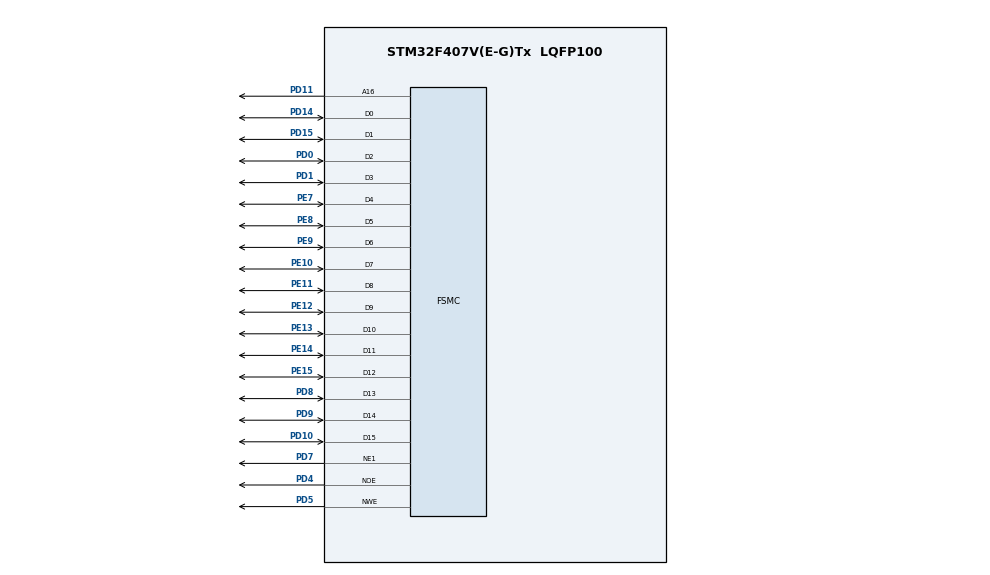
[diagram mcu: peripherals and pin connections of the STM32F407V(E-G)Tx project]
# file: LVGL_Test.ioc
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FSMC.ExtendedMode1=FSMC_EXTENDED_MODE_ENABLE
Mcu.Family=STM32F4
Mcu.Name=STM32F407V(E-G)Tx
Mcu.Package=LQFP100
NVIC.PriorityGroup=NVIC_PRIORITYGROUP_4
NVIC.TIM6_DAC_IRQn=true\:0\:0\:false\:false\:true\:true\:true
PA13.Mode=Serial_Wire
PA13.Signal=SYS_JTMS-SWDIO
PA14.Mode=Serial_Wire
PA14.Signal=SYS_JTCK-SWCLK
PD0.Mode=16b-d1
PD0.Signal=FSMC_D2
PD1.Mode=16b-d1
PD1.Signal=FSMC_D3
PD10.Mode=16b-d1
PD10.Signal=FSMC_D15
PD11.Mode=A16_1
PD11.Signal=FSMC_A16
PD14.Mode=16b-d1
PD14.Signal=FSMC_D0
PD15.Mode=16b-d1
PD15.Signal=FSMC_D1
PD4.Mode=Lcd1
PD4.Signal=FSMC_NOE
PD5.Mode=Lcd1
PD5.Signal=FSMC_NWE
PD7.Mode=NorPsramChipSelect1_1
PD7.Signal=FSMC_NE1
PD8.Mode=16b-d1
PD8.Signal=FSMC_D13
PD9.Mode=16b-d1
PD9.Signal=FSMC_D14
PE10.Mode=16b-d1
PE10.Signal=FSMC_D7
PE11.Mode=16b-d1
PE11.Signal=FSMC_D8
PE12.Mode=16b-d1
PE12.Signal=FSMC_D9
PE13.Mode=16b-d1
PE13.Signal=FSMC_D10
PE14.Mode=16b-d1
PE14.Signal=FSMC_D11
PE15.Mode=16b-d1
PE15.Signal=FSMC_D12
PE7.Mode=16b-d1
PE7.Signal=FSMC_D4
PE8.Mode=16b-d1
PE8.Signal=FSMC_D5
PE9.Mode=16b-d1
PE9.Signal=FSMC_D6
PH0-OSC_IN.Mode=HSE-External-Oscillator
PH0-OSC_IN.Signal=RCC_OSC_IN
PH1-OSC_OUT.Mode=HSE-External-Oscillator
PH1-OSC_OUT.Signal=RCC_OSC_OUT
ProjectManager.HeapSize=0x200
ProjectManager.StackSize=0x1000
ProjectManager.TargetToolchain=MDK-ARM V5
RCC.48MHZClocksFreq_Value=84000000
RCC.AHBFreq_Value=168000000
RCC.APB1CLKDivider=RCC_HCLK_DIV4
RCC.APB1Freq_Value=42000000
RCC.APB1TimFreq_Value=84000000
RCC.APB2CLKDivider=RCC_HCLK_DIV2
RCC.APB2Freq_Value=84000000
RCC.APB2TimFreq_Value=168000000
RCC.CortexFreq_Value=168000000
RCC.HCLKFreq_Value=168000000
RCC.HSE_VALUE=25000000
RCC.HSI_VALUE=16000000
RCC.LSE_VALUE=32768
RCC.PLLM=8
RCC.PLLN=168
RCC.SYSCLKFreq_VALUE=168000000
RCC.SYSCLKSource=RCC_SYSCLKSOURCE_PLLCLK
RCC.VCOOutputFreq_Value=336000000
TIM6.AutoReloadPreload=TIM_AUTORELOAD_PRELOAD_ENABLE
TIM6.Period=1000-1
TIM6.Prescaler=72-1
VP_TIM6_VS_ClockSourceINT.Mode=Enable_Timer
board=custom

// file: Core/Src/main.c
/* USER CODE BEGIN Header */
/**
  ******************************************************************************
  * @file           : main.c
  * @brief          : Main program body
  ******************************************************************************
  * @attention
  *
  * Copyright (c) 2025 STMicroelectronics.
  * All rights reserved.
  *
  * This software is licensed under terms that can be found in the LICENSE file
  * in the root directory of this software component.
  * If no LICENSE file comes with this software, it is provided AS-IS.
  *
  ******************************************************************************
  */
/* USER CODE END Header */
#include "main.h"
#include "tim.h"
#include "gpio.h"
#include "fsmc.h"
#include "lcd.h"

void SystemClock_Config(void);

int main(void)
{
  /* USER CODE BEGIN 1 */
  uint8_t x=0;
  uint8_t lcd_id[12];				//存放LCD ID字符串
  /* USER CODE END 1 */

  /* MCU Configuration--------------------------------------------------------*/

  /* Reset of all peripherals, Initializes the Flash interface and the Systick. */
  HAL_Init();

  /* USER CODE BEGIN Init */
  LCD_Init();           //初始化LCD FSMC接口
  POINT_COLOR=RED;      //画笔颜色：红色
  /* USER CODE END Init */

  /* Configure the system clock */
  SystemClock_Config();

  /* Initialize all configured peripherals */
  MX_GPIO_Init();
  MX_TIM6_Init();
  // MX_FSMC_Init();

  /* Infinite loop */
  while (1)
  {

    /* USER CODE BEGIN 3 */
	    switch(x)
		{
			case 0:LCD_Clear(WHITE);break;
			case 1:LCD_Clear(BLACK);break;
			case 2:LCD_Clear(BLUE);break;
			case 3:LCD_Clear(RED);break;
			case 4:LCD_Clear(MAGENTA);break;
			case 5:LCD_Clear(GREEN);break;
			case 6:LCD_Clear(CYAN);break;
			case 7:LCD_Clear(YELLOW);break;
			case 8:LCD_Clear(BRRED);break;
			case 9:LCD_Clear(GRAY);break;
			case 10:LCD_Clear(LGRAY);break;
			case 11:LCD_Clear(BROWN);break;
		}
		POINT_COLOR=RED;
		LCD_ShowString(30,40,210,24,24,"STM32F4 ARM-M4");
		LCD_ShowString(30,70,200,16,16,"FSMC TFTLCD TEST");
		LCD_ShowString(30,90,200,16,16,"Three blue whales");
 		LCD_ShowString(30,110,200,16,16,lcd_id);		//显示LCD ID
		LCD_ShowString(30,130,200,12,12,"2012/5/18");
        LCD_ShowString(30,250,210,24,24,"chinanuedc");
        LCD_ShowString(30,280,210,24,24,"taobao.com");
	    x++;
		if(x==12)x=0;
		//HAL_GPIO_TogglePin(LCD_BL_GPIO_Port, LCD_BL_Pin);
		HAL_Delay(1000);
  }
  /* USER CODE END 3 */
}

void SystemClock_Config(void)
{
  RCC_OscInitTypeDef RCC_OscInitStruct = {0};
  RCC_ClkInitTypeDef RCC_ClkInitStruct = {0};

  /** Configure the main internal regulator output voltage
  */
  __HAL_RCC_PWR_CLK_ENABLE();
  __HAL_PWR_VOLTAGESCALING_CONFIG(PWR_REGULATOR_VOLTAGE_SCALE1);
  /** Initializes the RCC Oscillators according to the specified parameters
  * in the RCC_OscInitTypeDef structure.
  */
  RCC_OscInitStruct.OscillatorType = RCC_OSCILLATORTYPE_HSI;
  RCC_OscInitStruct.HSIState = RCC_HSI_ON;
  RCC_OscInitStruct.HSICalibrationValue = RCC_HSICALIBRATION_DEFAULT;
  RCC_OscInitStruct.PLL.PLLState = RCC_PLL_ON;
  RCC_OscInitStruct.PLL.PLLSource = RCC_PLLSOURCE_HSI;
  RCC_OscInitStruct.PLL.PLLM = 8;
  RCC_OscInitStruct.PLL.PLLN = 72;
  RCC_OscInitStruct.PLL.PLLP = RCC_PLLP_DIV2;
  RCC_OscInitStruct.PLL.PLLQ = 4;
  if (HAL_RCC_OscConfig(&RCC_OscInitStruct) != HAL_OK)
  {
    Error_Handler();
  }
  /** Initializes the CPU, AHB and APB buses clocks
  */
  RCC_ClkInitStruct.ClockType = RCC_CLOCKTYPE_HCLK|RCC_CLOCKTYPE_SYSCLK
                              |RCC_CLOCKTYPE_PCLK1|RCC_CLOCKTYPE_PCLK2;
  RCC_ClkInitStruct.SYSCLKSource = RCC_SYSCLKSOURCE_PLLCLK;
  RCC_ClkInitStruct.AHBCLKDivider = RCC_SYSCLK_DIV1;
  RCC_ClkInitStruct.APB1CLKDivider = RCC_HCLK_DIV2;
  RCC_ClkInitStruct.APB2CLKDivider = RCC_HCLK_DIV1;

  if (HAL_RCC_ClockConfig(&RCC_ClkInitStruct, FLASH_LATENCY_2) != HAL_OK)
  {
    Error_Handler();
  }
}

void Error_Handler(void)
{
  __disable_irq();
  while (1)
  {
  }
}
